VERSION 5.7 ;
  NOWIREEXTENSIONATPIN ON ;
  DIVIDERCHAR "/" ;
  BUSBITCHARS "[]" ;
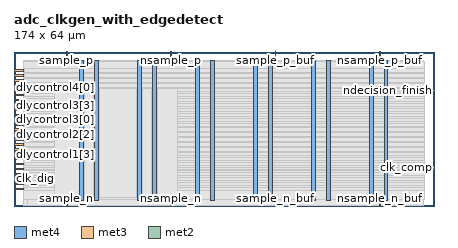
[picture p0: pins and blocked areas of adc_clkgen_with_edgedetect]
MACRO adc_clkgen_with_edgedetect
  CLASS BLOCK ;
  FOREIGN adc_clkgen_with_edgedetect ;
  ORIGIN 0.000 0.000 ;
  SIZE 174.000 BY 64.000 ;
  PIN VGND
    DIRECTION INOUT ;
    USE GROUND ;
    PORT
      LAYER met4 ;
        RECT 33.340 2.480 34.940 60.080 ;
    END
    PORT
      LAYER met4 ;
        RECT 57.340 2.480 58.940 60.080 ;
    END
    PORT
      LAYER met4 ;
        RECT 81.340 2.480 82.940 60.080 ;
    END
    PORT
      LAYER met4 ;
        RECT 105.340 2.480 106.940 60.080 ;
    END
    PORT
      LAYER met4 ;
        RECT 129.340 2.480 130.940 60.080 ;
    END
    PORT
      LAYER met4 ;
        RECT 153.340 2.480 154.940 60.080 ;
    END
  END VGND
  PIN VPWR
    DIRECTION INOUT ;
    USE POWER ;
    PORT
      LAYER met4 ;
        RECT 27.340 2.480 28.940 60.080 ;
    END
    PORT
      LAYER met4 ;
        RECT 51.340 2.480 52.940 60.080 ;
    END
    PORT
      LAYER met4 ;
        RECT 75.340 2.480 76.940 60.080 ;
    END
    PORT
      LAYER met4 ;
        RECT 99.340 2.480 100.940 60.080 ;
    END
    PORT
      LAYER met4 ;
        RECT 123.340 2.480 124.940 60.080 ;
    END
    PORT
      LAYER met4 ;
        RECT 147.340 2.480 148.940 60.080 ;
    END
  END VPWR
  PIN clk_comp
    DIRECTION OUTPUT TRISTATE ;
    USE SIGNAL ;
    PORT
      LAYER met3 ;
        RECT 170.000 15.680 174.000 16.280 ;
    END
  END clk_comp
  PIN clk_dig
    DIRECTION OUTPUT TRISTATE ;
    USE SIGNAL ;
    PORT
      LAYER met3 ;
        RECT 0.000 10.920 4.000 11.520 ;
    END
  END clk_dig
  PIN dlycontrol1[0]
    DIRECTION INPUT ;
    USE SIGNAL ;
    PORT
      LAYER met3 ;
        RECT 0.000 15.000 4.000 15.600 ;
    END
  END dlycontrol1[0]
  PIN dlycontrol1[1]
    DIRECTION INPUT ;
    USE SIGNAL ;
    PORT
      LAYER met3 ;
        RECT 0.000 17.040 4.000 17.640 ;
    END
  END dlycontrol1[1]
  PIN dlycontrol1[2]
    DIRECTION INPUT ;
    USE SIGNAL ;
    PORT
      LAYER met3 ;
        RECT 0.000 19.080 4.000 19.680 ;
    END
  END dlycontrol1[2]
  PIN dlycontrol1[3]
    DIRECTION INPUT ;
    USE SIGNAL ;
    PORT
      LAYER met3 ;
        RECT 0.000 21.120 4.000 21.720 ;
    END
  END dlycontrol1[3]
  PIN dlycontrol1[4]
    DIRECTION INPUT ;
    USE SIGNAL ;
    PORT
      LAYER met3 ;
        RECT 0.000 23.160 4.000 23.760 ;
    END
  END dlycontrol1[4]
  PIN dlycontrol2[0]
    DIRECTION INPUT ;
    USE SIGNAL ;
    PORT
      LAYER met3 ;
        RECT 0.000 25.200 4.000 25.800 ;
    END
  END dlycontrol2[0]
  PIN dlycontrol2[1]
    DIRECTION INPUT ;
    USE SIGNAL ;
    PORT
      LAYER met3 ;
        RECT 0.000 27.240 4.000 27.840 ;
    END
  END dlycontrol2[1]
  PIN dlycontrol2[2]
    DIRECTION INPUT ;
    USE SIGNAL ;
    PORT
      LAYER met3 ;
        RECT 0.000 29.280 4.000 29.880 ;
    END
  END dlycontrol2[2]
  PIN dlycontrol2[3]
    DIRECTION INPUT ;
    USE SIGNAL ;
    PORT
      LAYER met3 ;
        RECT 0.000 31.320 4.000 31.920 ;
    END
  END dlycontrol2[3]
  PIN dlycontrol2[4]
    DIRECTION INPUT ;
    USE SIGNAL ;
    PORT
      LAYER met3 ;
        RECT 0.000 33.360 4.000 33.960 ;
    END
  END dlycontrol2[4]
  PIN dlycontrol3[0]
    DIRECTION INPUT ;
    USE SIGNAL ;
    PORT
      LAYER met3 ;
        RECT 0.000 35.400 4.000 36.000 ;
    END
  END dlycontrol3[0]
  PIN dlycontrol3[1]
    DIRECTION INPUT ;
    USE SIGNAL ;
    PORT
      LAYER met3 ;
        RECT 0.000 37.440 4.000 38.040 ;
    END
  END dlycontrol3[1]
  PIN dlycontrol3[2]
    DIRECTION INPUT ;
    USE SIGNAL ;
    PORT
      LAYER met3 ;
        RECT 0.000 39.480 4.000 40.080 ;
    END
  END dlycontrol3[2]
  PIN dlycontrol3[3]
    DIRECTION INPUT ;
    USE SIGNAL ;
    PORT
      LAYER met3 ;
        RECT 0.000 41.520 4.000 42.120 ;
    END
  END dlycontrol3[3]
  PIN dlycontrol3[4]
    DIRECTION INPUT ;
    USE SIGNAL ;
    PORT
      LAYER met3 ;
        RECT 0.000 43.560 4.000 44.160 ;
    END
  END dlycontrol3[4]
  PIN dlycontrol4[0]
    DIRECTION INPUT ;
    USE SIGNAL ;
    PORT
      LAYER met3 ;
        RECT 0.000 45.600 4.000 46.200 ;
    END
  END dlycontrol4[0]
  PIN dlycontrol4[1]
    DIRECTION INPUT ;
    USE SIGNAL ;
    PORT
      LAYER met3 ;
        RECT 0.000 47.640 4.000 48.240 ;
    END
  END dlycontrol4[1]
  PIN dlycontrol4[2]
    DIRECTION INPUT ;
    USE SIGNAL ;
    PORT
      LAYER met3 ;
        RECT 0.000 49.680 4.000 50.280 ;
    END
  END dlycontrol4[2]
  PIN dlycontrol4[3]
    DIRECTION INPUT ;
    USE SIGNAL ;
    PORT
      LAYER met3 ;
        RECT 0.000 51.720 4.000 52.320 ;
    END
  END dlycontrol4[3]
  PIN dlycontrol4[4]
    DIRECTION INPUT ;
    USE SIGNAL ;
    PORT
      LAYER met3 ;
        RECT 0.000 53.760 4.000 54.360 ;
    END
  END dlycontrol4[4]
  PIN dlycontrol4[5]
    DIRECTION INPUT ;
    USE SIGNAL ;
    PORT
      LAYER met3 ;
        RECT 0.000 55.800 4.000 56.400 ;
    END
  END dlycontrol4[5]
  PIN ena_in
    DIRECTION INPUT ;
    USE SIGNAL ;
    PORT
      LAYER met3 ;
        RECT 0.000 6.840 4.000 7.440 ;
    END
  END ena_in
  PIN enable_dlycontrol
    DIRECTION INPUT ;
    USE SIGNAL ;
    PORT
      LAYER met3 ;
        RECT 0.000 12.960 4.000 13.560 ;
    END
  END enable_dlycontrol
  PIN ndecision_finish
    DIRECTION INPUT ;
    USE SIGNAL ;
    PORT
      LAYER met3 ;
        RECT 170.000 47.640 174.000 48.240 ;
    END
  END ndecision_finish
  PIN nsample_n
    DIRECTION INPUT ;
    USE SIGNAL ;
    PORT
      LAYER met2 ;
        RECT 64.950 0.000 65.230 4.000 ;
    END
  END nsample_n
  PIN nsample_n_buf
    DIRECTION OUTPUT TRISTATE ;
    USE SIGNAL ;
    PORT
      LAYER met2 ;
        RECT 151.430 0.000 151.710 4.000 ;
    END
  END nsample_n_buf
  PIN nsample_p
    DIRECTION INPUT ;
    USE SIGNAL ;
    PORT
      LAYER met2 ;
        RECT 64.950 60.000 65.230 64.000 ;
    END
  END nsample_p
  PIN nsample_p_buf
    DIRECTION OUTPUT TRISTATE ;
    USE SIGNAL ;
    PORT
      LAYER met2 ;
        RECT 151.430 60.000 151.710 64.000 ;
    END
  END nsample_p_buf
  PIN sample_n
    DIRECTION INPUT ;
    USE SIGNAL ;
    PORT
      LAYER met2 ;
        RECT 21.710 0.000 21.990 4.000 ;
    END
  END sample_n
  PIN sample_n_buf
    DIRECTION OUTPUT TRISTATE ;
    USE SIGNAL ;
    PORT
      LAYER met2 ;
        RECT 108.190 0.000 108.470 4.000 ;
    END
  END sample_n_buf
  PIN sample_p
    DIRECTION INPUT ;
    USE SIGNAL ;
    PORT
      LAYER met2 ;
        RECT 21.710 60.000 21.990 64.000 ;
    END
  END sample_p
  PIN sample_p_buf
    DIRECTION OUTPUT TRISTATE ;
    USE SIGNAL ;
    PORT
      LAYER met2 ;
        RECT 108.190 60.000 108.470 64.000 ;
    END
  END sample_p_buf
  PIN start_conv
    DIRECTION INPUT ;
    USE SIGNAL ;
    PORT
      LAYER met3 ;
        RECT 0.000 8.880 4.000 9.480 ;
    END
  END start_conv
  OBS
      LAYER li1 ;
        RECT 4.140 2.635 169.740 59.925 ;
      LAYER met1 ;
        RECT 4.140 0.040 169.740 60.080 ;
      LAYER met2 ;
        RECT 5.620 59.720 21.430 60.025 ;
        RECT 22.270 59.720 64.670 60.025 ;
        RECT 65.510 59.720 107.910 60.025 ;
        RECT 108.750 59.720 151.150 60.025 ;
        RECT 151.990 59.720 166.880 60.025 ;
        RECT 5.620 4.280 166.880 59.720 ;
        RECT 5.620 0.010 21.430 4.280 ;
        RECT 22.270 0.010 64.670 4.280 ;
        RECT 65.510 0.010 107.910 4.280 ;
        RECT 108.750 0.010 151.150 4.280 ;
        RECT 151.990 0.010 166.880 4.280 ;
      LAYER met3 ;
        RECT 4.000 56.800 170.000 60.005 ;
        RECT 4.400 55.400 170.000 56.800 ;
        RECT 4.000 54.760 170.000 55.400 ;
        RECT 4.400 53.360 170.000 54.760 ;
        RECT 4.000 52.720 170.000 53.360 ;
        RECT 4.400 51.320 170.000 52.720 ;
        RECT 4.000 50.680 170.000 51.320 ;
        RECT 4.400 49.280 170.000 50.680 ;
        RECT 4.000 48.640 170.000 49.280 ;
        RECT 4.400 47.240 169.600 48.640 ;
        RECT 4.000 46.600 170.000 47.240 ;
        RECT 4.400 45.200 170.000 46.600 ;
        RECT 4.000 44.560 170.000 45.200 ;
        RECT 4.400 43.160 170.000 44.560 ;
        RECT 4.000 42.520 170.000 43.160 ;
        RECT 4.400 41.120 170.000 42.520 ;
        RECT 4.000 40.480 170.000 41.120 ;
        RECT 4.400 39.080 170.000 40.480 ;
        RECT 4.000 38.440 170.000 39.080 ;
        RECT 4.400 37.040 170.000 38.440 ;
        RECT 4.000 36.400 170.000 37.040 ;
        RECT 4.400 35.000 170.000 36.400 ;
        RECT 4.000 34.360 170.000 35.000 ;
        RECT 4.400 32.960 170.000 34.360 ;
        RECT 4.000 32.320 170.000 32.960 ;
        RECT 4.400 30.920 170.000 32.320 ;
        RECT 4.000 30.280 170.000 30.920 ;
        RECT 4.400 28.880 170.000 30.280 ;
        RECT 4.000 28.240 170.000 28.880 ;
        RECT 4.400 26.840 170.000 28.240 ;
        RECT 4.000 26.200 170.000 26.840 ;
        RECT 4.400 24.800 170.000 26.200 ;
        RECT 4.000 24.160 170.000 24.800 ;
        RECT 4.400 22.760 170.000 24.160 ;
        RECT 4.000 22.120 170.000 22.760 ;
        RECT 4.400 20.720 170.000 22.120 ;
        RECT 4.000 20.080 170.000 20.720 ;
        RECT 4.400 18.680 170.000 20.080 ;
        RECT 4.000 18.040 170.000 18.680 ;
        RECT 4.400 16.680 170.000 18.040 ;
        RECT 4.400 16.640 169.600 16.680 ;
        RECT 4.000 16.000 169.600 16.640 ;
        RECT 4.400 15.280 169.600 16.000 ;
        RECT 4.400 14.600 170.000 15.280 ;
        RECT 4.000 13.960 170.000 14.600 ;
        RECT 4.400 12.560 170.000 13.960 ;
        RECT 4.000 11.920 170.000 12.560 ;
        RECT 4.400 10.520 170.000 11.920 ;
        RECT 4.000 9.880 170.000 10.520 ;
        RECT 4.400 8.480 170.000 9.880 ;
        RECT 4.000 7.840 170.000 8.480 ;
        RECT 4.400 6.440 170.000 7.840 ;
        RECT 4.000 2.555 170.000 6.440 ;
      LAYER met4 ;
        RECT 16.855 3.575 26.940 48.785 ;
        RECT 29.340 3.575 32.940 48.785 ;
        RECT 35.340 3.575 50.940 48.785 ;
        RECT 53.340 3.575 56.940 48.785 ;
        RECT 59.340 3.575 67.785 48.785 ;
  END
END adc_clkgen_with_edgedetect
END LIBRARY

